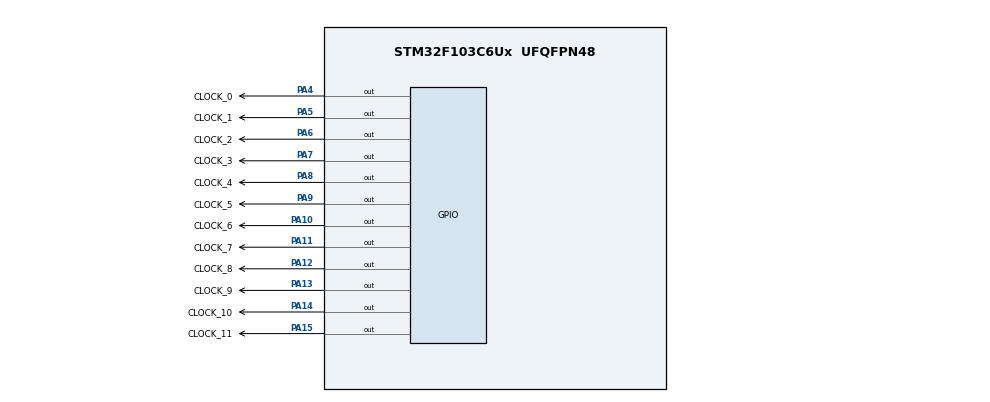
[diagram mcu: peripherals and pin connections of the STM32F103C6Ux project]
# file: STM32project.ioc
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Mcu.Family=STM32F1
Mcu.Name=STM32F103C6Ux
Mcu.Package=UFQFPN48
NVIC.PriorityGroup=NVIC_PRIORITYGROUP_4
PA10.GPIO_Label=CLOCK_6
PA10.Signal=GPIO_Output
PA11.GPIO_Label=CLOCK_7
PA11.Signal=GPIO_Output
PA12.GPIO_Label=CLOCK_8
PA12.Signal=GPIO_Output
PA13.GPIO_Label=CLOCK_9
PA13.Signal=GPIO_Output
PA14.GPIO_Label=CLOCK_10
PA14.Signal=GPIO_Output
PA15.GPIO_Label=CLOCK_11
PA15.Signal=GPIO_Output
PA4.GPIO_Label=CLOCK_0
PA4.Signal=GPIO_Output
PA5.GPIO_Label=CLOCK_1
PA5.Signal=GPIO_Output
PA6.GPIO_Label=CLOCK_2
PA6.Signal=GPIO_Output
PA7.GPIO_Label=CLOCK_3
PA7.Signal=GPIO_Output
PA8.GPIO_Label=CLOCK_4
PA8.Signal=GPIO_Output
PA9.GPIO_Label=CLOCK_5
PA9.Signal=GPIO_Output
ProjectManager.HeapSize=0x200
ProjectManager.StackSize=0x400
ProjectManager.TargetToolchain=STM32CubeIDE
RCC.APB1Freq_Value=8000000
RCC.APB2Freq_Value=8000000
VP_SYS_VS_ND.Mode=No_Debug
board=custom

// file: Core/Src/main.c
/* USER CODE BEGIN Header */
/**
  ******************************************************************************
  * @file           : main.c
  * @brief          : Main program body
  ******************************************************************************
  * @attention
  *
  * <h2><center>&copy; Copyright (c) 2023 STMicroelectronics.
  * All rights reserved.</center></h2>
  *
  * This software component is licensed by ST under BSD 3-Clause license,
  * the "License"; You may not use this file except in compliance with the
  * License. You may obtain a copy of the License at:
  *                        opensource.org/licenses/BSD-3-Clause
  *
  ******************************************************************************
  */
/* USER CODE END Header */
#include "main.h"

void SystemClock_Config(void);
static void MX_GPIO_Init(void);
void display7SEG(int num);

int main(void)
{

  /* MCU Configuration--------------------------------------------------------*/

  /* Reset of all peripherals, Initializes the Flash interface and the Systick. */
  HAL_Init();

  /* Configure the system clock */
  SystemClock_Config();

  /* Initialize all configured peripherals */
  MX_GPIO_Init();

  /* Infinite loop */
  /* USER CODE BEGIN WHILE */
  HAL_GPIO_WritePin(LED_RED_HORIZONTAL_GPIO_Port, LED_RED_HORIZONTAL_Pin, SET);
  HAL_GPIO_WritePin(LED_YELLOW_HORIZONTAL_GPIO_Port, LED_YELLOW_HORIZONTAL_Pin , SET);
  HAL_GPIO_WritePin(LED_GREEN_HORIZONTAL_GPIO_Port, LED_GREEN_HORIZONTAL_Pin, SET);
  HAL_GPIO_WritePin(LED_RED_VERTICAL_GPIO_Port, LED_RED_VERTICAL_Pin, SET);
  HAL_GPIO_WritePin(LED_YELLOW_VERTICAL_GPIO_Port, LED_YELLOW_VERTICAL_Pin, SET);
  HAL_GPIO_WritePin(LED_GREEN_VERTICAL_GPIO_Port, LED_GREEN_VERTICAL_Pin, SET);
  HAL_GPIO_WritePin(a_GPIO_Port, a_Pin, SET);
  HAL_GPIO_WritePin(b_GPIO_Port, b_Pin, SET);
  HAL_GPIO_WritePin(c_GPIO_Port, c_Pin, SET);
  HAL_GPIO_WritePin(d_GPIO_Port, d_Pin, SET);
  HAL_GPIO_WritePin(e_GPIO_Port, e_Pin, SET);
  HAL_GPIO_WritePin(f_GPIO_Port, f_Pin, SET);
  HAL_GPIO_WritePin(g_GPIO_Port, g_Pin, SET);
  int red_timer = 5, green_timer = 3;
  int led_counter = 5;
  int state = 0;
  while (1)
  {
	  display7SEG(led_counter);
	  switch (state) {
	  	  case 0: //GREEN Vertical: ON, RED Horizontal: ON
	  		HAL_GPIO_WritePin(LED_GREEN_VERTICAL_GPIO_Port, LED_GREEN_VERTICAL_Pin, RESET);
	  		HAL_GPIO_WritePin(LED_RED_HORIZONTAL_GPIO_Port, LED_RED_HORIZONTAL_Pin, RESET);
	  		HAL_GPIO_WritePin(LED_YELLOW_HORIZONTAL_GPIO_Port, LED_YELLOW_HORIZONTAL_Pin , SET);
	  		HAL_GPIO_WritePin(LED_RED_VERTICAL_GPIO_Port, LED_RED_VERTICAL_Pin, SET);
	  		led_counter--;
	  		if (led_counter < green_timer) {
	  			state = 1;
	  		}
	  		break;
	  	  case 1: //YELLOW Vertical: ON, RED Horizontal: ON
	  		HAL_GPIO_WritePin(LED_YELLOW_VERTICAL_GPIO_Port, LED_YELLOW_VERTICAL_Pin, RESET);
	  		HAL_GPIO_WritePin(LED_GREEN_VERTICAL_GPIO_Port, LED_GREEN_VERTICAL_Pin, SET);
	  		led_counter--;
	  		if (led_counter < -0.01) {
	  			state = 2;
	  			led_counter = green_timer;
	  		}
	  		break;
	  	  case 2://RED Vertical: ON, GREEN Horizontal: ON
	  		HAL_GPIO_WritePin(LED_YELLOW_VERTICAL_GPIO_Port, LED_YELLOW_VERTICAL_Pin, SET);
	  		HAL_GPIO_WritePin(LED_RED_VERTICAL_GPIO_Port, LED_RED_VERTICAL_Pin, RESET);
	  		HAL_GPIO_WritePin(LED_GREEN_HORIZONTAL_GPIO_Port, LED_GREEN_HORIZONTAL_Pin, RESET);
	  		HAL_GPIO_WritePin(LED_RED_HORIZONTAL_GPIO_Port, LED_RED_HORIZONTAL_Pin, SET);
	  		led_counter--;
	  		if (led_counter <= 0) {
	  			state = 3;
	  		}
	  		break;
	  	  case 3://RED Vertical: ON, YELLOW Horizontal: ON
	  		HAL_GPIO_WritePin(LED_YELLOW_HORIZONTAL_GPIO_Port, LED_YELLOW_HORIZONTAL_Pin , RESET);
	  		HAL_GPIO_WritePin(LED_GREEN_HORIZONTAL_GPIO_Port, LED_GREEN_HORIZONTAL_Pin, SET);
	  		led_counter--;
	  		if (led_counter < -0.01) {
	  			state = 0;
	  			led_counter = red_timer;
	  		}
	  		break;
	  }
	  HAL_Delay(1000);

    /* USER CODE END WHILE */

  }
}

void SystemClock_Config(void)
{
  RCC_OscInitTypeDef RCC_OscInitStruct = {0};
  RCC_ClkInitTypeDef RCC_ClkInitStruct = {0};

  /** Initializes the RCC Oscillators according to the specified parameters
  * in the RCC_OscInitTypeDef structure.
  */
  RCC_OscInitStruct.OscillatorType = RCC_OSCILLATORTYPE_HSI;
  RCC_OscInitStruct.HSIState = RCC_HSI_ON;
  RCC_OscInitStruct.HSICalibrationValue = RCC_HSICALIBRATION_DEFAULT;
  RCC_OscInitStruct.PLL.PLLState = RCC_PLL_NONE;
  if (HAL_RCC_OscConfig(&RCC_OscInitStruct) != HAL_OK)
  {
    Error_Handler();
  }
  /** Initializes the CPU, AHB and APB buses clocks
  */
  RCC_ClkInitStruct.ClockType = RCC_CLOCKTYPE_HCLK|RCC_CLOCKTYPE_SYSCLK
                              |RCC_CLOCKTYPE_PCLK1|RCC_CLOCKTYPE_PCLK2;
  RCC_ClkInitStruct.SYSCLKSource = RCC_SYSCLKSOURCE_HSI;
  RCC_ClkInitStruct.AHBCLKDivider = RCC_SYSCLK_DIV1;
  RCC_ClkInitStruct.APB1CLKDivider = RCC_HCLK_DIV1;
  RCC_ClkInitStruct.APB2CLKDivider = RCC_HCLK_DIV1;

  if (HAL_RCC_ClockConfig(&RCC_ClkInitStruct, FLASH_LATENCY_0) != HAL_OK)
  {
    Error_Handler();
  }
}

static void MX_GPIO_Init(void)
{
  GPIO_InitTypeDef GPIO_InitStruct = {0};

  /* GPIO Ports Clock Enable */
  __HAL_RCC_GPIOA_CLK_ENABLE();
  __HAL_RCC_GPIOB_CLK_ENABLE();

  /*Configure GPIO pin Output Level */
  HAL_GPIO_WritePin(GPIOA, LED_RED_VERTICAL_Pin|LED_YELLOW_VERTICAL_Pin|LED_GREEN_VERTICAL_Pin|LED_RED_HORIZONTAL_Pin
                          |LED_YELLOW_HORIZONTAL_Pin|LED_GREEN_HORIZONTAL_Pin, GPIO_PIN_RESET);

  /*Configure GPIO pin Output Level */
  HAL_GPIO_WritePin(GPIOB, a_Pin|b_Pin|c_Pin|d_Pin
                          |e_Pin|f_Pin|g_Pin, GPIO_PIN_RESET);

  /*Configure GPIO pins : LED_RED_VERTICAL_Pin LED_YELLOW_VERTICAL_Pin LED_GREEN_VERTICAL_Pin LED_RED_HORIZONTAL_Pin
                           LED_YELLOW_HORIZONTAL_Pin LED_GREEN_HORIZONTAL_Pin */
  GPIO_InitStruct.Pin = LED_RED_VERTICAL_Pin|LED_YELLOW_VERTICAL_Pin|LED_GREEN_VERTICAL_Pin|LED_RED_HORIZONTAL_Pin
                          |LED_YELLOW_HORIZONTAL_Pin|LED_GREEN_HORIZONTAL_Pin;
  GPIO_InitStruct.Mode = GPIO_MODE_OUTPUT_PP;
  GPIO_InitStruct.Pull = GPIO_NOPULL;
  GPIO_InitStruct.Speed = GPIO_SPEED_FREQ_LOW;
  HAL_GPIO_Init(GPIOA, &GPIO_InitStruct);

  /*Configure GPIO pins : a_Pin b_Pin c_Pin d_Pin
                           e_Pin f_Pin g_Pin */
  GPIO_InitStruct.Pin = a_Pin|b_Pin|c_Pin|d_Pin
                          |e_Pin|f_Pin|g_Pin;
  GPIO_InitStruct.Mode = GPIO_MODE_OUTPUT_PP;
  GPIO_InitStruct.Pull = GPIO_NOPULL;
  GPIO_InitStruct.Speed = GPIO_SPEED_FREQ_LOW;
  HAL_GPIO_Init(GPIOB, &GPIO_InitStruct);

}

void display7SEG(int num) {
	switch(num){
	    	  	  	case 0:
	    				  HAL_GPIO_WritePin(a_GPIO_Port, a_Pin, RESET);
	    				  HAL_GPIO_WritePin(b_GPIO_Port, b_Pin, RESET);
	    				  HAL_GPIO_WritePin(c_GPIO_Port, c_Pin, RESET);
	    				  HAL_GPIO_WritePin(d_GPIO_Port, d_Pin, RESET);
	    				  HAL_GPIO_WritePin(e_GPIO_Port, e_Pin, RESET);
	    				  HAL_GPIO_WritePin(f_GPIO_Port, f_Pin, RESET);
	    				  HAL_GPIO_WritePin(g_GPIO_Port, g_Pin, SET);
	    				  break;
	    	  		case 1:
	    				  HAL_GPIO_WritePin(a_GPIO_Port, a_Pin, SET);
	    				  HAL_GPIO_WritePin(b_GPIO_Port, b_Pin, RESET);
	    				  HAL_GPIO_WritePin(c_GPIO_Port, c_Pin, RESET);
	    				  HAL_GPIO_WritePin(d_GPIO_Port, d_Pin, SET);
	    				  HAL_GPIO_WritePin(e_GPIO_Port, e_Pin, SET);
	    				  HAL_GPIO_WritePin(f_GPIO_Port, f_Pin, SET);
	    				  HAL_GPIO_WritePin(g_GPIO_Port, g_Pin, SET);
	    				  break;
	    	  		case 2:
	    				  HAL_GPIO_WritePin(a_GPIO_Port, a_Pin, RESET);
	    				  HAL_GPIO_WritePin(b_GPIO_Port, b_Pin, RESET);
	    				  HAL_GPIO_WritePin(c_GPIO_Port, c_Pin, SET);
	    				  HAL_GPIO_WritePin(d_GPIO_Port, d_Pin, RESET);
	    				  HAL_GPIO_WritePin(e_GPIO_Port, e_Pin, RESET);
	    				  HAL_GPIO_WritePin(f_GPIO_Port, f_Pin, SET);
	    				  HAL_GPIO_WritePin(g_GPIO_Port, g_Pin, RESET);
	    				  break;
	    	  		case 3:
	    				  HAL_GPIO_WritePin(a_GPIO_Port, a_Pin, RESET);
	    				  HAL_GPIO_WritePin(b_GPIO_Port, b_Pin, RESET);
	    				  HAL_GPIO_WritePin(c_GPIO_Port, c_Pin, RESET);
	    				  HAL_GPIO_WritePin(d_GPIO_Port, d_Pin, RESET);
	    				  HAL_GPIO_WritePin(e_GPIO_Port, e_Pin, SET);
	    				  HAL_GPIO_WritePin(f_GPIO_Port, f_Pin, SET);
	    				  HAL_GPIO_WritePin(g_GPIO_Port, g_Pin, RESET);
	    				  break;
	    	  		case 4:
	    		  		  HAL_GPIO_WritePin(a_GPIO_Port, a_Pin, SET);
	    				  HAL_GPIO_WritePin(b_GPIO_Port, b_Pin, RESET);
	    				  HAL_GPIO_WritePin(c_GPIO_Port, c_Pin, RESET);
	    				  HAL_GPIO_WritePin(d_GPIO_Port, d_Pin, SET);
	    				  HAL_GPIO_WritePin(e_GPIO_Port, e_Pin, SET);
	    				  HAL_GPIO_WritePin(f_GPIO_Port, f_Pin, RESET);
	    				  HAL_GPIO_WritePin(g_GPIO_Port, g_Pin, RESET);
	    				  break;
	    			case 5:
	    				  HAL_GPIO_WritePin(a_GPIO_Port, a_Pin, RESET);
	    				  HAL_GPIO_WritePin(b_GPIO_Port, b_Pin, SET);
	    				  HAL_GPIO_WritePin(c_GPIO_Port, c_Pin, RESET);
	    				  HAL_GPIO_WritePin(d_GPIO_Port, d_Pin, RESET);
	    				  HAL_GPIO_WritePin(e_GPIO_Port, e_Pin, SET);
	    				  HAL_GPIO_WritePin(f_GPIO_Port, f_Pin, RESET);
	    				  HAL_GPIO_WritePin(g_GPIO_Port, g_Pin, RESET);
	    				  break;
	    			case 6:
	    				  HAL_GPIO_WritePin(a_GPIO_Port, a_Pin, RESET);
	    				  HAL_GPIO_WritePin(b_GPIO_Port, b_Pin, SET);
	    				  HAL_GPIO_WritePin(c_GPIO_Port, c_Pin, RESET);
	    				  HAL_GPIO_WritePin(d_GPIO_Port, d_Pin, RESET);
	    				  HAL_GPIO_WritePin(e_GPIO_Port, e_Pin, RESET);
	    				  HAL_GPIO_WritePin(f_GPIO_Port, f_Pin, RESET);
	    				  HAL_GPIO_WritePin(g_GPIO_Port, g_Pin, RESET);
	    				  break;
	    			case 7:
	    				  HAL_GPIO_WritePin(a_GPIO_Port, a_Pin, RESET);
	    				  HAL_GPIO_WritePin(b_GPIO_Port, b_Pin, RESET);
	    				  HAL_GPIO_WritePin(c_GPIO_Port, c_Pin, RESET);
	    				  HAL_GPIO_WritePin(d_GPIO_Port, d_Pin, SET);
	    				  HAL_GPIO_WritePin(e_GPIO_Port, e_Pin, SET);
	    				  HAL_GPIO_WritePin(f_GPIO_Port, f_Pin, SET);
	    				  HAL_GPIO_WritePin(g_GPIO_Port, g_Pin, SET);
	    				  break;
	    			case 8:
	    				  HAL_GPIO_WritePin(a_GPIO_Port, a_Pin, RESET);
	    				  HAL_GPIO_WritePin(b_GPIO_Port, b_Pin, RESET);
	    				  HAL_GPIO_WritePin(c_GPIO_Port, c_Pin, RESET);
	    				  HAL_GPIO_WritePin(d_GPIO_Port, d_Pin, RESET);
	    				  HAL_GPIO_WritePin(e_GPIO_Port, e_Pin, RESET);
	    				  HAL_GPIO_WritePin(f_GPIO_Port, f_Pin, RESET);
	    				  HAL_GPIO_WritePin(g_GPIO_Port, g_Pin, RESET);
	    				  break;
	    			case 9:
	    				  HAL_GPIO_WritePin(a_GPIO_Port, a_Pin, RESET);
	    				  HAL_GPIO_WritePin(b_GPIO_Port, b_Pin, RESET);
	    				  HAL_GPIO_WritePin(c_GPIO_Port, c_Pin, RESET);
	    				  HAL_GPIO_WritePin(d_GPIO_Port, d_Pin, RESET);
	    				  HAL_GPIO_WritePin(e_GPIO_Port, e_Pin, SET);
	    				  HAL_GPIO_WritePin(f_GPIO_Port, f_Pin, RESET);
	    				  HAL_GPIO_WritePin(g_GPIO_Port, g_Pin, RESET);
	    				  break;
	}
}

void Error_Handler(void)
{
  __disable_irq();
  while (1)
  {
  }
}

/************************ (C) COPYRIGHT STMicroelectronics *****END OF FILE****/
